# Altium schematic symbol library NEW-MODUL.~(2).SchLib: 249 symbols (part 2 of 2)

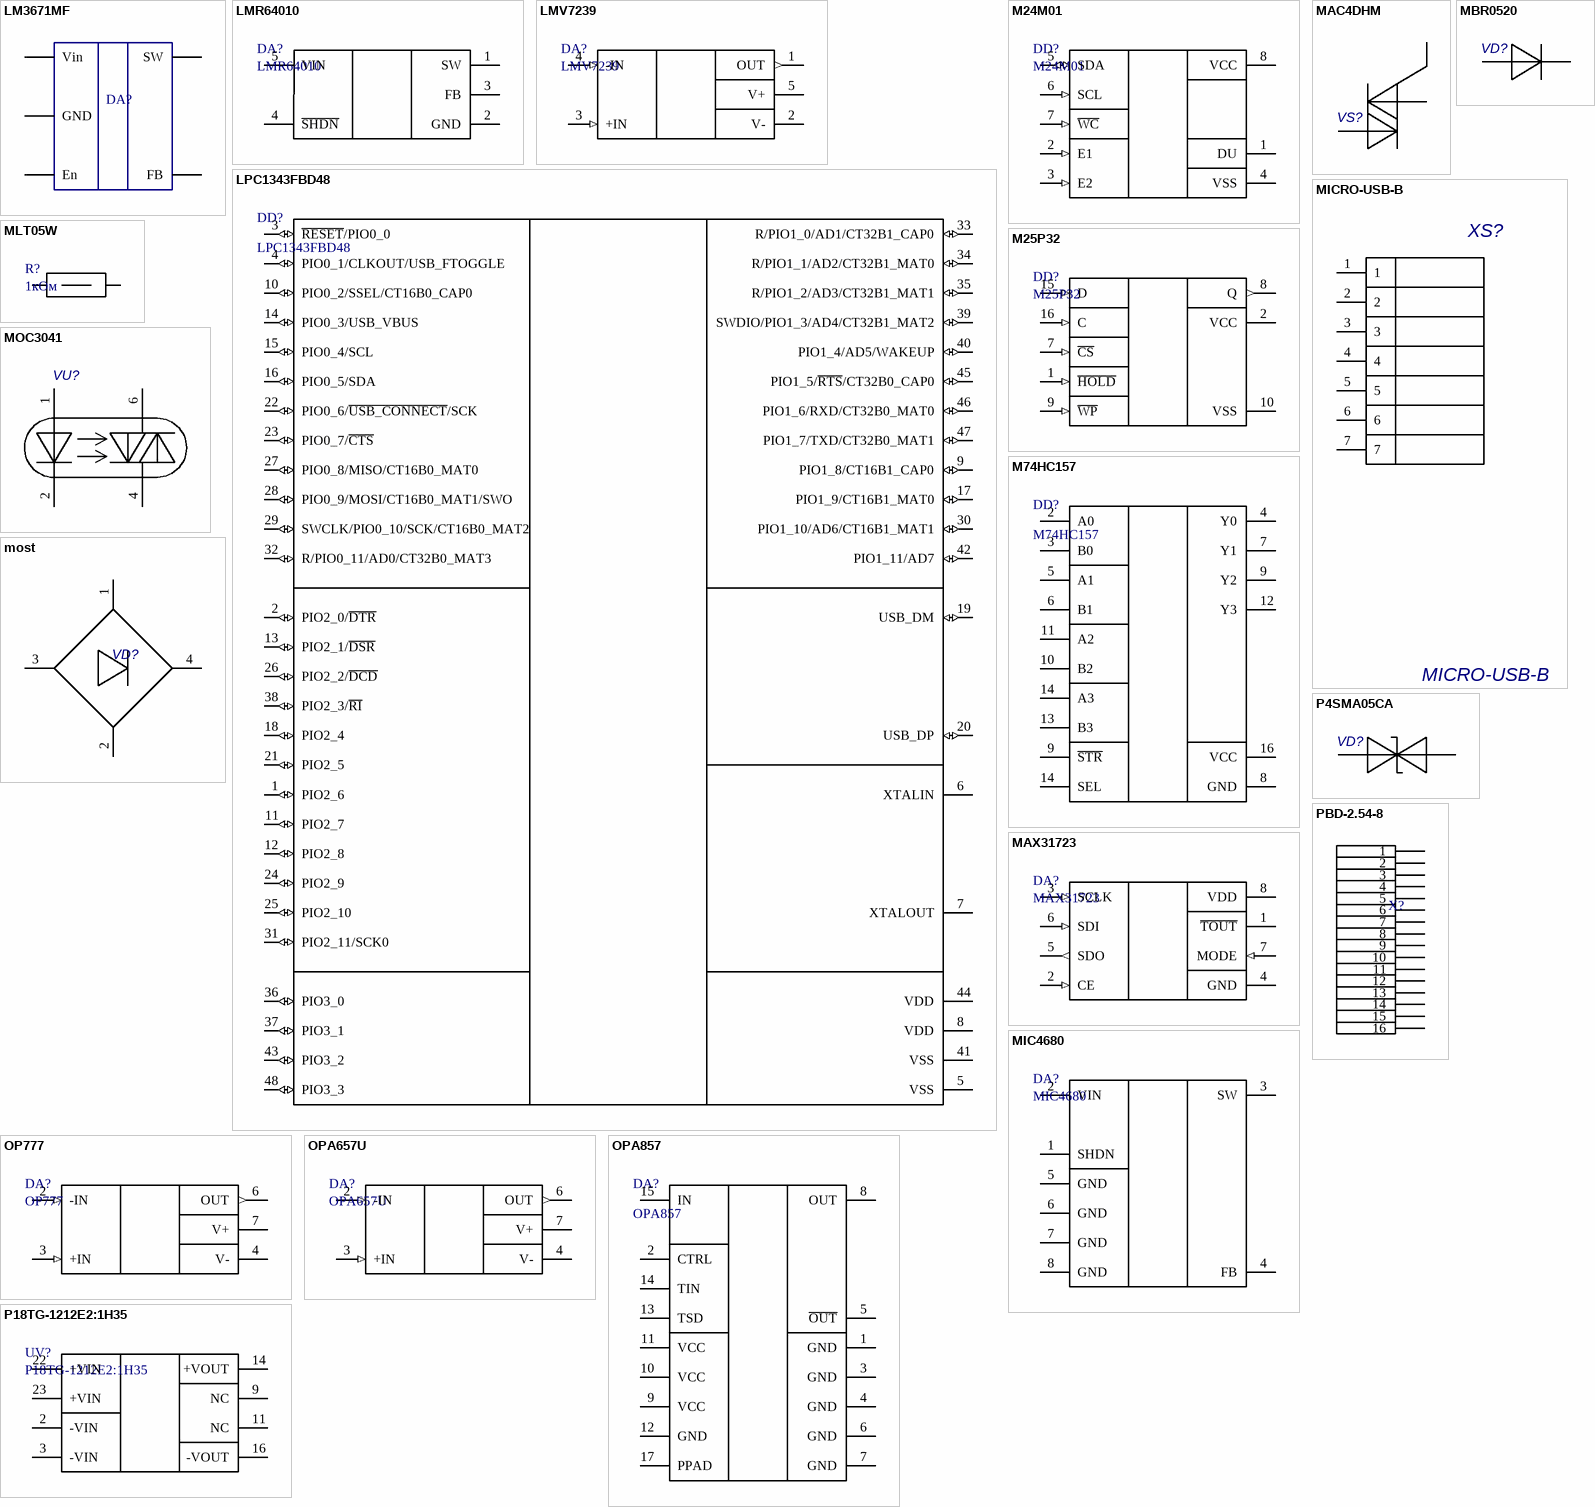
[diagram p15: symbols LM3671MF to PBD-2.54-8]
## LMR64010
designator DA?
footprint SOT23-5AM (SOT23, 5-Leads, Body 2.9x1.7mm, Pitch 0.95mm, Lead Span 2.8mm, IPC Low Density)
pins: 1 SW, 2 GND (power), 3 FB, 4 ~{SHDN}, 5 VIN (power)

## LMV7239
designator DA?
Comparator with Open-Drain/Push-Pull Output
footprint SOT23-5AM (SOT23, 5-Leads, Body 2.9x1.7mm, Pitch 0.95mm, Lead Span 2.8mm, IPC Low Density)
pins: 1 OUT (out), 2 V- (power), 3 +IN (in), 4 -IN (in), 5 V+ (power)

## LPC1343FBD48
designator DD?
Cortex-M3, 32-Bit ARM MCU, 32 kB flash, 8 kB SRAM, 72 MHz USB device, 48-Pin LQFP; fmax: 72 MHz; SRAM: 8 kB; Flash: 32 kB; GPIOs: 40; USB: 1; PLL: Y; ADC channels: 8; Timers: 4; VDD (min): 2 V; VDD (typ): 3.3 V; VDD (max): 3.6 V; Code_IEC: 136E05
footprint SOT313-2_V (Thin QFP, 48-Leads, Body 7x7mm, Pitch 0.5mm, NXP Recommended)
pins: 1 PIO2_6 (io), 2 PIO2_0/~{DTR} (io), 3 ~{RESET}/PIO0_0 (io), 4 PIO0_1/CLKOUT/USB_FTOGGLE (io), 5 VSS (power), 6 XTALIN, 7 XTALOUT, 8 VDD (power), 9 PIO1_8/CT16B1_CAP0 (io), 10 PIO0_2/SSEL/CT16B0_CAP0 (io), 11 PIO2_7 (io), 12 PIO2_8 (io), 13 PIO2_1/~{DSR} (io), 14 PIO0_3/USB_VBUS (io), 15 PIO0_4/SCL (io), 16 PIO0_5/SDA (io), 17 PIO1_9/CT16B1_MAT0 (io), 18 PIO2_4 (io), 19 USB_DM (io), 20 USB_DP (io), 21 PIO2_5 (io), 22 PIO0_6/~{USB_CONNECT}/SCK (io), 23 PIO0_7/~{CTS} (io), 24 PIO2_9 (io), 25 PIO2_10 (io), 26 PIO2_2/~{DCD} (io), 27 PIO0_8/MISO/CT16B0_MAT0 (io), 28 PIO0_9/MOSI/CT16B0_MAT1/SWO (io), 29 SWCLK/PIO0_10/SCK/CT16B0_MAT2 (io), 30 PIO1_10/AD6/CT16B1_MAT1 (io), 31 PIO2_11/SCK0 (io), 32 R/PIO0_11/AD0/CT32B0_MAT3 (io), 33 R/PIO1_0/AD1/CT32B1_CAP0 (io), 34 R/PIO1_1/AD2/CT32B1_MAT0 (io), 35 R/PIO1_2/AD3/CT32B1_MAT1 (io), 36 PIO3_0 (io), 37 PIO3_1 (io), 38 PIO2_3/~{RI} (io), 39 SWDIO/PIO1_3/AD4/CT32B1_MAT2 (io), 40 PIO1_4/AD5/WAKEUP (io), 41 VSS (power), 42 PIO1_11/AD7 (io), 43 PIO3_2 (io), 44 VDD (power), 45 PIO1_5/~{RTS}/CT32B0_CAP0 (io), 46 PIO1_6/RXD/CT32B0_MAT0 (io), 47 PIO1_7/TXD/CT32B0_MAT1 (io), 48 PIO3_3 (io)

## M24M01
designator DD?
footprint SOIC127P600-8BM (SOIC, 8-Leads, Body 4.9x3.9mm, Pitch 1.27mm, IPC Low Density)
pins: 1 DU, 2 E1 (in), 3 E2 (in), 4 VSS (power), 5 SDA (io), 6 SCL (in), 7 ~{WC} (in), 8 VCC (power)

## M25P32
designator DD?
footprint DW016_N (16-Pin Plastic Small Outline Integrated Circuit 1.27 mm Pitch, IPC Medium Density)
pins: 1 ~{HOLD} (in), 2 VCC (power), 7 ~{CS} (in), 8 Q (out), 9 ~{WP} (in), 10 VSS, 15 D (in), 16 C (in)

## M74HC157
designator DD?
footprint R-16A_M (16-Pin Small Outline Integrated Circuit 1.27 mm Pitch, IPC Low Density)
pins: 2 A0, 3 B0, 4 Y0, 5 A1, 6 B1, 7 Y1, 8 GND, 9 ~{STR}, 9 Y2, 10 B2, 11 A2, 12 Y3, 13 B3, 14 SEL, 14 A3, 16 VCC

## MAC4DHM
designator VS?  (value not drawn)
Sensitive Gate Triacs  Silicon Bidirectional Thyristors
footprint ONSC-DPAK-3-369AA-01_V (DPAK, 3-Leads, Body 6.54x6.095mm, Pitch 2.29mm)
pins: 1 MT1, 3 GATE, 4 MT2

## MAX31723
designator DA?
footprint UMAX8 (Shrink Small Outline; 8 Leads; Body Width 3 mm; Pitch 0.65 mm)
pins: 1 ~{TOUT} (oc), 2 CE (in), 3 SCLK (in), 4 GND (power), 5 SDO (out), 6 SDI (in), 7 MODE (in), 8 VDD (power)

## MBR0520
designator VD?  (value not drawn)
Silicon Switching Diode Array for High-Speed Switching
footprint sod123
pins: 1 A, 2 C

## MIC4680
designator DA?
footprint SOIC127P600-8BM (SOIC, 8-Leads, Body 4.9x3.9mm, Pitch 1.27mm, IPC Low Density)
pins: 1 SHDN, 2 VIN, 3 SW, 4 FB, 5 GND, 6 GND, 7 GND, 8 GND

## MICRO-USB-B
designator XS?
footprint MICRO-USB-B
pins: 1, 2, 3, 4, 5, 6, 7, 8 hidden, 9 hidden, 10 hidden, 11 hidden

## MLT05W
designator R?, comment 1кОм
резистор 0,5W
footprint MLT05WT
pins: 1, 2

## MOC3041
designator VU?  (value not drawn)
footprint DIP6-320
pins: 1, 2, 4, 6

## most
designator VD?  (value not drawn)
Silicon Switching Diode Array for High-Speed Switching
pins: 1, 2, 3, 4

## OP777
designator DA?
Precision Micropower  Single-Supply Operational Amplifiers
footprint SOIC127P600-8BM (SOIC, 8-Leads, Body 4.9x3.9mm, Pitch 1.27mm, IPC Low Density)
pins: 2 -IN (in), 3 +IN (in), 4 V- (power), 6 OUT (out), 7 V+ (power)

## OPA657U
designator DA?
FET OP
footprint SOIC127P600-8BM (SOIC, 8-Leads, Body 4.9x3.9mm, Pitch 1.27mm, IPC Low Density)
pins: 2 -IN (in), 3 +IN (in), 4 V- (power), 6 OUT (out), 7 V+ (power)

## OPA857
designator DA?
footprint PV-QFN16 (QFN, 16-Leads, Body 3x3mm, Pitch 0.5mm, Thermal Pad 1.75x1.75mm, IPC Low Density)
pins: 1 GND, 2 CTRL, 3 GND, 4 GND, 5 ~{OUT}, 6 GND, 7 GND, 8 OUT, 9 VCC, 10 VCC, 11 VCC, 12 GND, 13 TSD, 14 TIN, 15 IN, 17 PPAD

## P4SMA05CA
designator VD?  (value not drawn)
Silicon Switching Diode Array for High-Speed Switching
footprint SMA
pins: 1 A, 2

## P18TG-1212E2:1H35
designator UV?
DC-DC 12V-12V 4WT
footprint P18TG-1212E2:1H35
pins: 2 -VIN (power), 3 -VIN (power), 9 NC, 11 NC, 14 +VOUT (power), 16 -VOUT, 22 +VIN (power), 23 +VIN

## PBD-2.54-8
designator X?, comment pbd  (value not drawn)
footprint PBD
pins: 1, 2, 3, 4, 5, 6, 7, 8, 9, 10, 11, 12, 13, 14, 15, 16


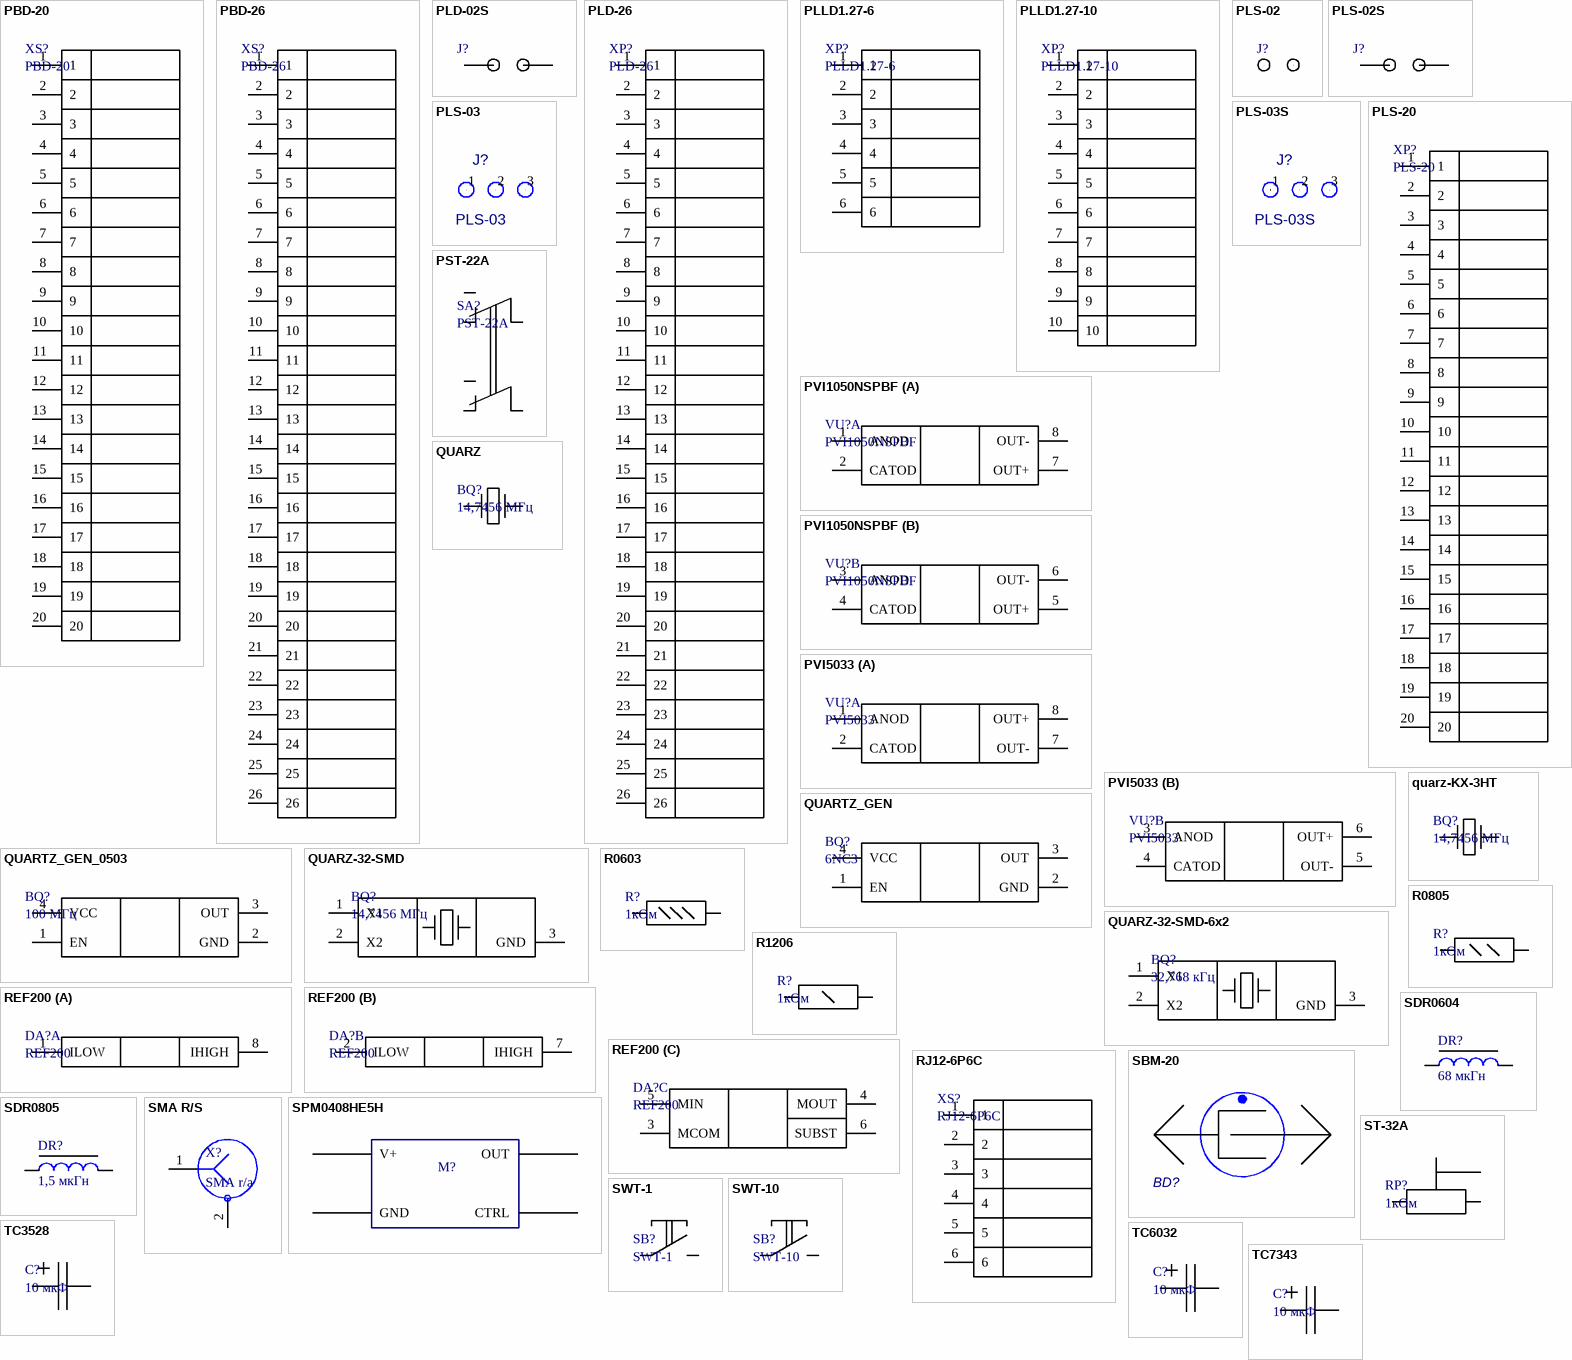
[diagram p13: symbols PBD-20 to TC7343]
## PBD-20
designator XS?
footprint PBD-20 (Connector; IDC, Low Profile Male Header, Thru-Hole; 10 Position; Vertical; Pitch 2.54 mm)
pins: 1, 2, 3, 4, 5, 6, 7, 8, 9, 10, 11, 12, 13, 14, 15, 16, 17, 18, 19, 20

## PBD-26
designator XS?
footprint PBD-26 (Connector; IDC, Low Profile Male Header, Thru-Hole; 10 Position; Vertical; Pitch 2.54 mm)
pins: 1, 2, 3, 4, 5, 6, 7, 8, 9, 10, 11, 12, 13, 14, 15, 16, 17, 18, 19, 20, 21, 22, 23, 24, 25, 26

## PLD-02S
designator J?  (value not drawn)
footprint PLD-02S
pins: 1, 2

## PLD-26
designator XP?
footprint PLD-26 (Connector; IDC, Low Profile Male Header, Thru-Hole; 26 Position; Vertical; Pitch 2.54 mm)
pins: 1, 2, 3, 4, 5, 6, 7, 8, 9, 10, 11, 12, 13, 14, 15, 16, 17, 18, 19, 20, 21, 22, 23, 24, 25, 26

## PLLD1.27-6
designator XP?
footprint PLLD1.27-6
pins: 1, 2, 3, 4, 5, 6

## PLLD1.27-10
designator XP?
footprint PLLD1.27-10
pins: 1, 2, 3, 4, 5, 6, 7, 8, 9, 10

## PLS-02
designator J?  (value not drawn)
footprint Jump2
pins: 1, 2

## PLS-02S
designator J?  (value not drawn)
footprint PLS-02S
pins: 1, 2

## PLS-03
designator J?
PLS-03S
footprint JUMP3
pins: 1, 2, 3

## PLS-03S
designator J?
PDIF_TY: 255; PDIF_I_PID: JUMP2
footprint PLS-03S
pins: 1, 2, 3

## PLS-20
designator XP?
footprint PLS-20 (Connector; , Low Profile Male Header, Thru-Hole; 20 Position; Vertical; Pitch 2.54 mm)
pins: 1, 2, 3, 4, 5, 6, 7, 8, 9, 10, 11, 12, 13, 14, 15, 16, 17, 18, 19, 20

## PST-22A
designator SA?
footprint PST-22A
pins: 1 NC1, 2 COM1, 3 NO1, 4 NC2, 5 COM2, 6 NO2

## PVI1050NSPBF
designator VU?
Photovoltaic Isolator
footprint S-DIP-8 (DIP; 8 Trim Leads; Row Spacing 7.62 mm; Pitch 2.54 mm)
part A pins: 1 ANOD, 2 CATOD, 7 OUT+, 8 OUT-
part B pins: 3 ANOD, 4 CATOD, 5 OUT+, 6 OUT-

## PVI5033
designator VU?
OP
footprint S-DIP-8 (DIP; 8 Trim Leads; Row Spacing 7.62 mm; Pitch 2.54 mm)
part A pins: 1 ANOD, 2 CATOD, 7 OUT-, 8 OUT+
part B pins: 3 ANOD, 4 CATOD, 5 OUT-, 6 OUT+

## QUARTZ_GEN
designator BQ?, comment 6NC3
footprint 6NC3
pins: 1 EN, 2 GND, 3 OUT, 4 VCC

## QUARTZ_GEN_0503
designator BQ?, comment 100 МГц
footprint KXO-V99
pins: 1 EN, 2 GND, 3 OUT, 4 VCC

## QUARZ
designator BQ?, comment 14,7456 МГц
footprint HC49S-SMD
pins: 1, 2

## QUARZ-32-SMD
designator BQ?, comment 14,7456 МГц
footprint QURTZ-32-SMD
pins: 1 X1, 2 X2, 3 GND

## QUARZ-32-SMD-6x2
designator BQ?, comment 32,768 кГц
footprint QURTZ-32-SMD -6x2
pins: 1 X1, 2 X2, 3 GND

## quarz-KX-3HT
designator BQ?, comment 14,7456 МГц
footprint quarz-KX-3HT
pins: 1, 2

## R0603
designator R?, comment 1кОм
планарный резистор
footprint R0603
pins: 1, 2

## R0805
designator R?, comment 1кОм
планарный резистор
footprint RESC2012N (Chip Resistor, Body 2.0x1.3mm, IPC Medium Density)
pins: 1, 2

## R1206
designator R?, comment 1кОм
планарный резистор
footprint R1206
pins: 1, 2

## REF200
designator DA?
footprint SOIC127P600-8BM (SOIC, 8-Leads, Body 4.9x3.9mm, Pitch 1.27mm, IPC Low Density)
part A pins: 1 ILOW, 8 IHIGH
part B pins: 2 ILOW, 7 IHIGH
part C pins: 3 MCOM, 4 MOUT, 5 MIN, 6 SUBST

## RJ12-6P6C
designator XS?
555731-1
footprint JACK/SM1.27-2H6A (Connector; PCB Jack, SM; 1-Port, 6 Positions, 6 Loaded; Unshielded without Lightpipes; Right Angle)
pins: 1, 2, 3, 4, 5, 6

## SBM-20
designator BD?  (value not drawn)
footprint SBM-20

## SDR0604
designator DR?, comment 68 мкГн
inductor
footprint SDR0604
pins: 1, 2

## SDR0805
designator DR?, comment 1,5 мкГн
inductor
footprint SDR0805
pins: 1, 2

## SMA R/S
designator X?, comment SMA r/a
footprint SMA - duplicate
pins: 1, 2

## SPM0408HE5H
designator M?  (value not drawn)
footprint SPM0408HE5H
pins: 1 OUT, 2 CTRL, 3 GND, 4 V+

## ST-32A
designator RP?, comment 1кОм
подстроечный резистор
footprint ST-32A
pins: 1, 2, 3

## SWT-1
designator SB?
footprint SWT-1 (Switch, 2 Pin)
pins: 1, 2

## SWT-10
designator SB?
footprint SWT-10 (2-Leads, Body 6,0x3,5mm, IPC Medium Density)
pins: 1, 2

## TC3528
designator C?, comment 10 мкФ
конденсатор
footprint CAPC3225M (Chip Capacitor, Body 3.2x2.5mm, IPC Low Density)
pins: 1, 2

## TC6032
designator C?, comment 10 мкФ
конденсатор
footprint CAPC5734M (Chip Capacitor, Body 5.7x3.4mm, IPC Low Density)
pins: 1, 2

## TC7343
designator C?, comment 10 мкФ
конденсатор
footprint CAPC7238M (Chip Capacitor, Body 7.2x3.8mm, IPC Low Density)
pins: 1, 2


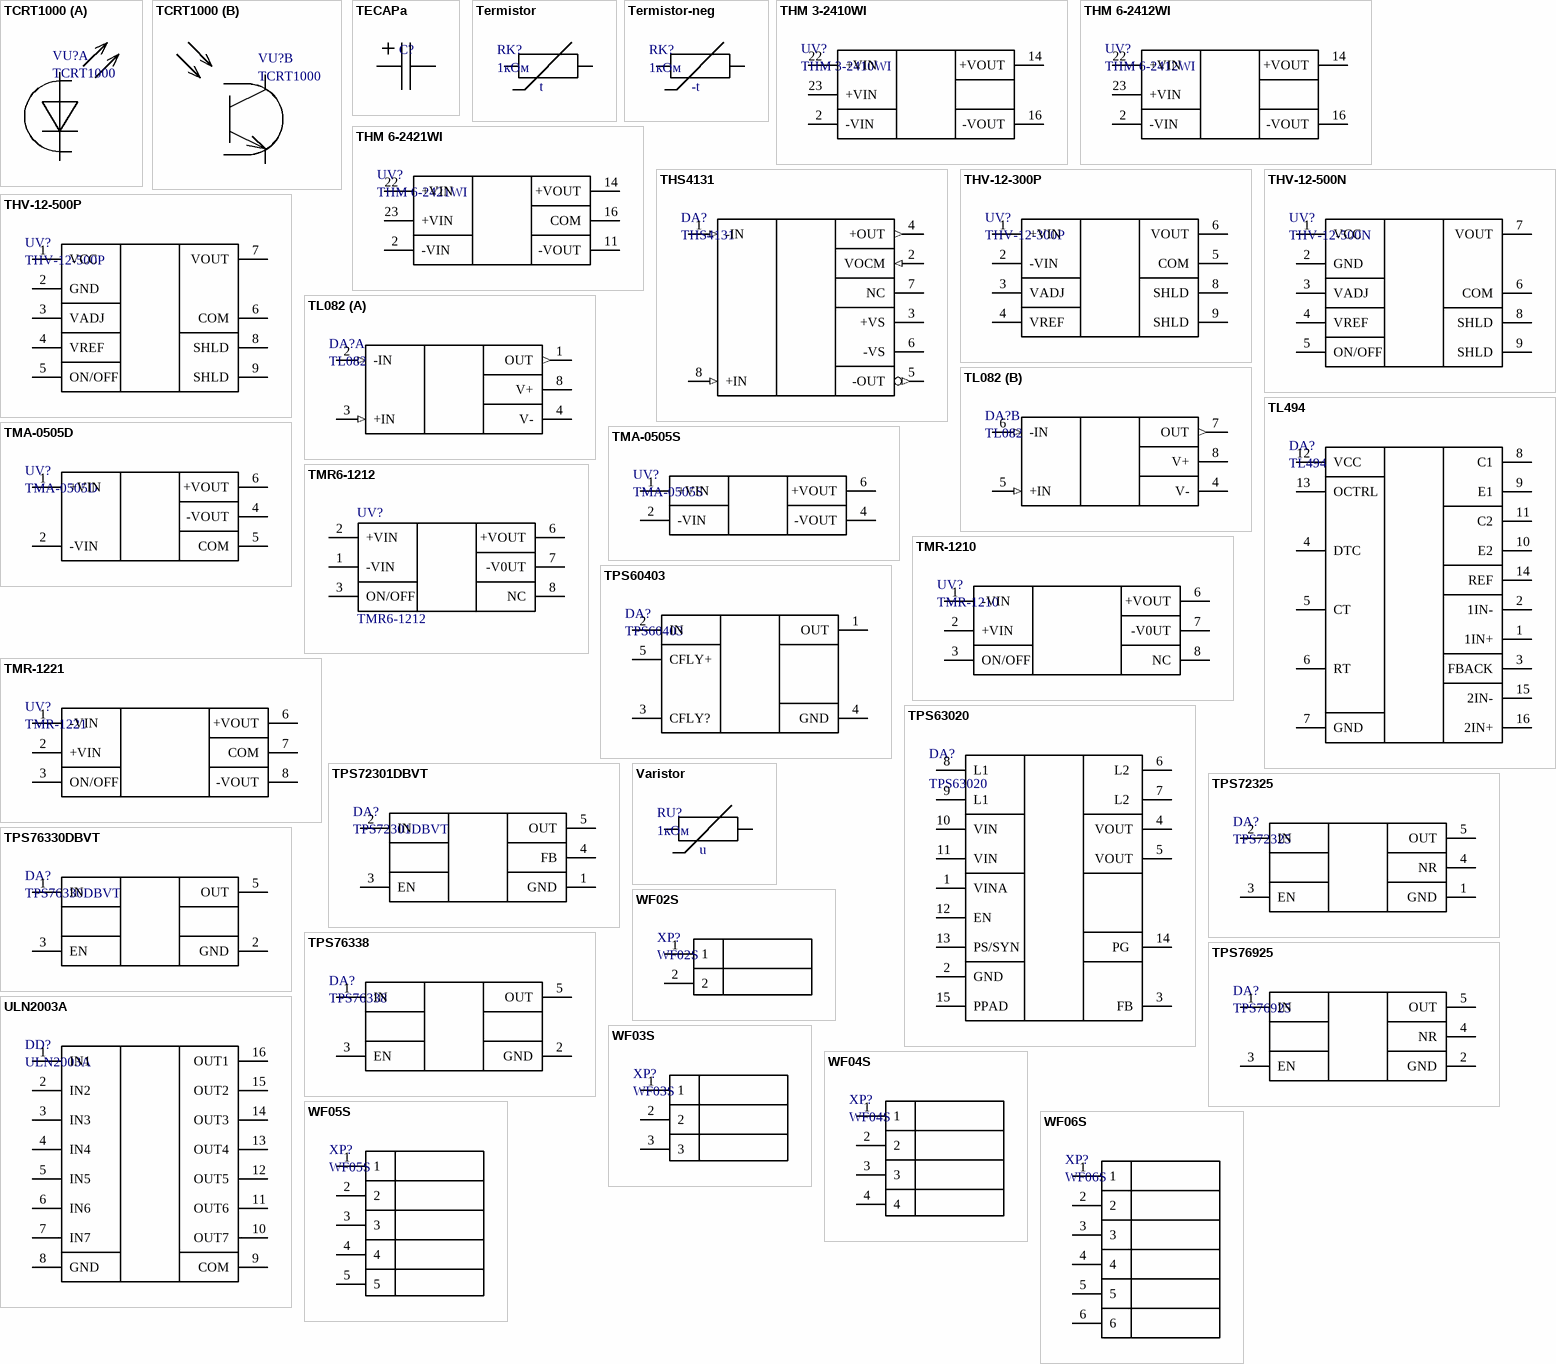
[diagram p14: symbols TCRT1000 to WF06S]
## TCRT1000
designator VU?
footprint TCRT1000
part A pins: 1 ANOD, 2 CATOD
part B pins: 3 EMITTER, 4 COLECTOR

## TECAPa
designator C?  (value not drawn)
footprint TECAPa
pins: 1, 2

## Termistor
designator RK?, comment 1кОм
планарный резистор
footprint RESC2012N (Chip Resistor, Body 2.0x1.3mm, IPC Medium Density)
pins: 1, 2

## Termistor-neg
designator RK?, comment 1кОм
планарный резистор
footprint RESC2012N (Chip Resistor, Body 2.0x1.3mm, IPC Medium Density)
pins: 1, 2

## THM 3-2410WI
designator UV?
regulated 3 Watt DC/DC  converters in a DIP-24 plastic package
footprint THM 3-2410WI
pins: 2 -VIN (power), 14 +VOUT (power), 16 -VOUT, 22 +VIN (power), 23 +VIN

## THM 6-2412WI
designator UV?
regulated 6 Watt DC/DC  converters in a DIP-24 plastic package
footprint THM 6-2412WI
pins: 2 -VIN (power), 14 +VOUT (power), 16 -VOUT, 22 +VIN (power), 23 +VIN

## THM 6-2421WI
designator UV?
regulated 6 Watt DC/DC  converters in a DIP-24 plastic package
footprint THM 6-2421WI
pins: 2 -VIN (power), 11 -VOUT, 14 +VOUT (power), 16 COM, 22 +VIN (power), 23 +VIN

## THS4131
designator DA?
Differential ADC driver
footprint SOIC127P600-8BM (SOIC, 8-Leads, Body 4.9x3.9mm, Pitch 1.27mm, IPC Low Density)
pins: 1 -IN (in), 2 VOCM (in), 3 +VS (power), 4 +OUT (out), 5 -OUT (out), 6 -VS (power), 7 NC, 8 +IN (in)

## THV-12-300P
designator UV?
footprint THV-CASEA
pins: 1 +VIN, 2 -VIN, 3 VADJ, 4 VREF, 5 COM, 6 VOUT, 8 SHLD, 9 SHLD

## THV-12-500N
designator UV?
footprint THV-CASEB
pins: 1 VCC, 2 GND, 3 VADJ, 4 VREF, 5 ON/OFF, 6 COM, 7 VOUT, 8 SHLD, 9 SHLD

## THV-12-500P
designator UV?
footprint THV-CASEB
pins: 1 VCC, 2 GND, 3 VADJ, 4 VREF, 5 ON/OFF, 6 COM, 7 VOUT, 8 SHLD, 9 SHLD

## TL082
designator DA?
OP
footprint SOIC127P600-8BM (SOIC, 8-Leads, Body 4.9x3.9mm, Pitch 1.27mm, IPC Low Density)
part A pins: 1 OUT (out), 2 -IN (in), 3 +IN (in), 4 V- (power), 8 V+ (power)
part B pins: 4 V- (power), 5 +IN (in), 6 -IN (in), 7 OUT (out), 8 V+ (power)

## TL494
designator DA?
footprint R-16A_M (16-Pin Small Outline Integrated Circuit 1.27 mm Pitch, IPC Low Density)
pins: 1 1IN+, 2 1IN-, 3 FBACK, 4 DTC, 5 CT, 6 RT, 7 GND, 8 C1, 9 E1, 10 E2, 11 C2, 12 VCC, 13 OCTRL, 14 REF, 15 2IN-, 16 2IN+

## TMA-0505D
designator UV?
footprint TMA0505S
pins: 1 +VIN (power), 2 -VIN (power), 4 -VOUT (power), 5 COM, 6 +VOUT (power)

## TMA-0505S
designator UV?
footprint TMA0505S
pins: 1 +VIN (power), 2 -VIN (power), 4 -VOUT (power), 6 +VOUT (power)

## TMR6-1212
designator UV?
footprint SIP8
pins: 1 -VIN, 2 +VIN, 3 ON/OFF, 6 +VOUT, 7 -V0UT, 8 NC

## TMR-1210
designator UV?
footprint SIP8
pins: 1 -VIN, 2 +VIN, 3 ON/OFF, 6 +VOUT, 7 -V0UT, 8 NC

## TMR-1221
designator UV?
footprint SIP8
pins: 1 -VIN, 2 +VIN, 3 ON/OFF, 6 +VOUT, 7 COM, 8 -VOUT

## TPS60403
designator DA?
The TPS6040x is a family of devices that generate an unregulated negative output voltage from an input voltage  ranging from 1.6 V to 5.5 V.
footprint SOT23-5AM (SOT23, 5-Leads, Body 2.9x1.7mm, Pitch 0.95mm, Lead Span 2.8mm, IPC Low Density)
pins: 1 OUT, 2 IN, 3 CFLY?, 4 GND, 5 CFLY+

## TPS63020
designator DA?
HIGH EFFICIENCY SINGLE INDUCTOR BUCK-BOOST CONVERTER WITH 4-A SWITCHES
footprint VSON-14 (PQFN, 24-Leads, Body 5x4mm, Pitch 0.5mm, NSC Recommended)
pins: 1 VINA, 2 GND, 3 FB, 4 VOUT, 5 VOUT, 6 L2 , 7 L2 , 8 L1, 9 L1, 10 VIN , 11 VIN , 12 EN, 13 PS/SYN, 14 PG , 15 PPAD

## TPS72301DBVT
designator DA?
The TPS723xx family of low-dropout (LDO) negative  voltage regulators
footprint SOT23-5AM (SOT23, 5-Leads, Body 2.9x1.7mm, Pitch 0.95mm, Lead Span 2.8mm, IPC Low Density)
pins: 1 GND, 2 IN, 3 EN, 4 FB, 5 OUT

## TPS72325
designator DA?
The TPS723xx family of low-dropout (LDO) negative  voltage regulators
footprint SOT23-5AM (SOT23, 5-Leads, Body 2.9x1.7mm, Pitch 0.95mm, Lead Span 2.8mm, IPC Low Density)
pins: 1 GND, 2 IN, 3 EN, 4 NR, 5 OUT

## TPS76330DBVT
designator DA?
The TPS723xx family of low-dropout (LDO)  voltage regulators
footprint SOT23-5AM (SOT23, 5-Leads, Body 2.9x1.7mm, Pitch 0.95mm, Lead Span 2.8mm, IPC Low Density)
pins: 1 IN, 2 GND, 3 EN, 5 OUT

## TPS76338
designator DA?
The TPS723xx family of low-dropout (LDO) negative  voltage regulators
footprint SOT23-5AM (SOT23, 5-Leads, Body 2.9x1.7mm, Pitch 0.95mm, Lead Span 2.8mm, IPC Low Density)
pins: 1 IN, 2 GND, 3 EN, 5 OUT

## TPS76925
designator DA?
The TPS723xx family of low-dropout (LDO) negative  voltage regulators
footprint SOT23-5AM (SOT23, 5-Leads, Body 2.9x1.7mm, Pitch 0.95mm, Lead Span 2.8mm, IPC Low Density)
pins: 1 IN, 2 GND, 3 EN, 4 NR, 5 OUT

## ULN2003A
designator DD?
7-Channel Relay and Inductive Load Sink Driver
footprint R-16A_M (16-Pin Small Outline Integrated Circuit 1.27 mm Pitch, IPC Low Density)
pins: 1 IN1, 2 IN2, 3 IN3, 4 IN4, 5 IN5, 6 IN6, 7 IN7, 8 GND, 9 COM, 10 OUT7, 11 OUT6, 12 OUT5, 13 OUT4, 14 OUT3, 15 OUT2, 16 OUT1

## Varistor
designator RU?, comment 1кОм
планарный резистор
footprint RESC2012N (Chip Resistor, Body 2.0x1.3mm, IPC Medium Density)
pins: 1, 2

## WF02S
designator XP?
footprint WF02S
pins: 1, 2

## WF03S
designator XP?
footprint WF03S
pins: 1, 2, 3

## WF04S
designator XP?
footprint WF04S
pins: 1, 2, 3, 4

## WF05S
designator XP?
footprint WF05S
pins: 1, 2, 3, 4, 5

## WF06S
designator XP?
footprint WF06S
pins: 1, 2, 3, 4, 5, 6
